VERSION 5.7 ;
  NOWIREEXTENSIONATPIN ON ;
  DIVIDERCHAR "/" ;
  BUSBITCHARS "[]" ;
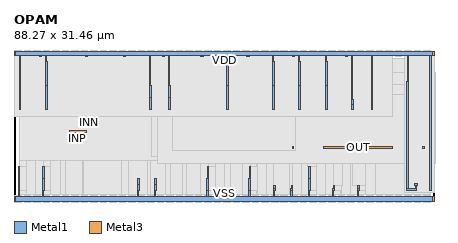
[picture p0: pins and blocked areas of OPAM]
MACRO OPAM
  CLASS BLOCK ;
  FOREIGN OPAM ;
  ORIGIN 1.260 0.000 ;
  SIZE 88.270 BY 31.460 ;
  PIN VSS
    DIRECTION INOUT ;
    USE GROUND ;
    PORT
      LAYER Metal1 ;
        RECT -0.360 4.730 0.000 7.230 ;
        RECT 4.800 4.730 5.160 7.230 ;
        RECT 39.330 4.730 39.690 7.230 ;
        RECT 48.150 4.730 48.510 7.230 ;
        RECT 60.630 4.730 60.990 7.230 ;
        RECT -0.390 2.230 0.000 4.730 ;
        RECT 4.770 2.230 5.160 4.730 ;
        RECT 24.690 3.480 25.050 4.730 ;
        RECT 28.350 3.480 28.710 4.730 ;
        RECT 24.660 2.230 25.050 3.480 ;
        RECT 28.320 2.230 28.710 3.480 ;
        RECT 39.300 2.230 39.690 4.730 ;
        RECT 48.120 2.230 48.510 4.730 ;
        RECT 53.310 2.730 53.670 3.230 ;
        RECT 56.970 2.730 57.330 3.230 ;
        RECT 53.280 2.230 53.670 2.730 ;
        RECT 56.940 2.230 57.330 2.730 ;
        RECT 60.600 2.230 60.990 4.730 ;
        RECT 65.790 2.730 66.150 3.230 ;
        RECT 70.950 2.730 71.310 3.230 ;
        RECT 65.760 2.230 66.150 2.730 ;
        RECT 70.920 2.230 71.310 2.730 ;
        RECT -0.390 0.900 -0.160 2.230 ;
        RECT 4.770 0.900 5.000 2.230 ;
        RECT 24.660 0.900 24.890 2.230 ;
        RECT 28.320 0.900 28.550 2.230 ;
        RECT 39.300 0.900 39.530 2.230 ;
        RECT 48.120 0.900 48.350 2.230 ;
        RECT 53.280 0.900 53.510 2.230 ;
        RECT 56.940 0.900 57.170 2.230 ;
        RECT 60.600 0.900 60.830 2.230 ;
        RECT 65.760 0.900 65.990 2.230 ;
        RECT 70.920 0.900 71.150 2.230 ;
        RECT -1.000 0.000 86.780 0.900 ;
      LAYER Metal3 ;
        RECT -1.260 0.000 87.010 0.900 ;
    END
  END VSS
  PIN VDD
    DIRECTION INOUT ;
    USE POWER ;
    PORT
      LAYER Metal1 ;
        RECT -1.000 30.560 86.780 31.460 ;
        RECT -0.190 29.230 0.040 30.560 ;
        RECT 4.050 30.460 4.530 30.560 ;
        RECT 5.370 29.230 5.600 30.560 ;
        RECT 13.670 30.460 14.150 30.560 ;
        RECT 21.790 30.460 22.270 30.560 ;
        RECT -0.190 24.230 0.200 29.230 ;
        RECT 5.370 24.230 5.760 29.230 ;
        RECT -0.160 19.230 0.200 24.230 ;
        RECT 5.400 19.230 5.760 24.230 ;
        RECT 27.170 24.230 27.400 30.560 ;
        RECT 29.910 30.460 30.390 30.560 ;
        RECT 31.230 24.230 31.460 30.560 ;
        RECT 38.030 30.460 38.510 30.560 ;
        RECT 43.410 29.230 43.640 30.560 ;
        RECT 47.650 30.460 48.130 30.560 ;
        RECT 53.030 29.230 53.260 30.560 ;
        RECT 57.270 30.460 57.750 30.560 ;
        RECT 58.590 29.230 58.820 30.560 ;
        RECT 64.150 29.230 64.380 30.560 ;
        RECT 68.390 30.460 68.870 30.560 ;
        RECT 43.410 24.230 43.800 29.230 ;
        RECT 53.030 24.230 53.420 29.230 ;
        RECT 58.590 24.230 58.980 29.230 ;
        RECT 64.150 24.230 64.540 29.230 ;
        RECT 27.170 21.730 27.560 24.230 ;
        RECT 31.230 21.730 31.620 24.230 ;
        RECT 27.200 19.230 27.560 21.730 ;
        RECT 31.260 19.230 31.620 21.730 ;
        RECT 43.440 19.230 43.800 24.230 ;
        RECT 53.060 19.230 53.420 24.230 ;
        RECT 58.620 19.230 58.980 24.230 ;
        RECT 64.180 19.230 64.540 24.230 ;
        RECT 69.710 21.230 69.940 30.560 ;
        RECT 73.770 29.230 74.000 30.560 ;
        RECT 73.770 24.230 74.160 29.230 ;
        RECT 81.355 25.190 81.585 30.560 ;
        RECT 69.710 20.230 70.100 21.230 ;
        RECT 69.740 19.230 70.100 20.230 ;
        RECT 73.800 19.230 74.160 24.230 ;
        RECT 81.320 2.530 81.620 25.190 ;
        RECT 82.900 3.280 83.600 3.640 ;
        RECT 83.100 2.530 83.400 3.280 ;
        RECT 81.320 2.230 83.400 2.530 ;
        RECT 86.030 2.230 86.510 30.560 ;
      LAYER Metal3 ;
        RECT -1.260 30.560 87.010 31.460 ;
    END
  END VDD
  PIN OUT
    DIRECTION INOUT ;
    ANTENNADIFFAREA 0.748000 ;
    PORT
      LAYER Metal3 ;
      RECT 57.185 11.050 57.585 11.450 ;
      RECT 63.885 11.050 78.385 11.450 ;
      RECT 84.685 11.050 85.085 11.450 ;
    END
  END OUT
  PIN INP
    DIRECTION INPUT ;
    ANTENNAGATEAREA 15.000000 ;
    PORT
      LAYER Metal3 ;
      RECT 10.390 14.350 13.990 14.750 ;
    END
  END INP
  PIN INN
    DIRECTION INPUT ;
    ANTENNAGATEAREA 15.000000 ;
    PORT
      LAYER Metal3 ;
      RECT 12.750 16.330 16.150 16.730 ;
    END
  END INN
  OBS
      LAYER Via1 ;
        RECT -0.160 1.420 86.310 30.040 ;
        RECT 53.260 29.220 54.720 30.040 ;
        RECT 58.820 29.220 60.280 30.040 ;
        RECT 64.380 29.220 65.840 30.040 ;
        RECT 74.000 29.220 75.460 30.040 ;
        RECT 43.640 29.220 45.100 30.040 ;
        RECT 42.850 30.320 44.230 31.700 ;
        RECT 44.850 30.320 46.230 31.700 ;
        RECT 46.850 30.320 48.230 31.700 ;
        RECT 48.850 30.320 50.230 31.700 ;
        RECT 50.850 30.320 52.230 31.700 ;
        RECT 52.850 30.320 54.230 31.700 ;
        RECT 54.850 30.320 56.230 31.700 ;
        RECT 56.850 30.320 58.230 31.700 ;
        RECT 58.850 30.320 60.230 31.700 ;
        RECT 60.850 30.320 62.230 31.700 ;
        RECT 62.850 30.320 64.230 31.700 ;
        RECT 64.850 30.320 66.230 31.700 ;
        RECT 66.850 30.320 68.230 31.700 ;
        RECT 68.850 30.320 70.230 31.700 ;
        RECT 70.850 30.320 72.230 31.700 ;
        RECT 72.850 30.320 74.230 31.700 ;
        RECT 74.850 30.320 76.230 31.700 ;
        RECT 76.850 30.320 78.230 31.700 ;
        RECT 78.850 30.320 80.230 31.700 ;
        RECT 80.850 30.320 82.230 31.700 ;
        RECT 82.850 30.320 84.230 31.700 ;
        RECT 84.850 30.320 86.230 31.700 ;
        RECT 38.850 30.320 40.230 31.700 ;
        RECT 40.850 30.320 42.230 31.700 ;
        RECT 0.040 29.220 1.500 30.040 ;
        RECT 5.600 29.220 7.060 30.040 ;
        RECT -1.150 30.320 0.230 31.700 ;
        RECT 0.850 30.320 2.230 31.700 ;
        RECT 2.850 30.320 4.230 31.700 ;
        RECT 4.850 30.320 6.230 31.700 ;
        RECT 6.850 30.320 8.230 31.700 ;
        RECT 8.850 30.320 10.230 31.700 ;
        RECT 10.850 30.320 12.230 31.700 ;
        RECT 12.850 30.320 14.230 31.700 ;
        RECT 14.850 30.320 16.230 31.700 ;
        RECT 16.850 30.320 18.230 31.700 ;
        RECT 18.850 30.320 20.230 31.700 ;
        RECT 20.850 30.320 22.230 31.700 ;
        RECT 22.850 30.320 24.230 31.700 ;
        RECT 24.850 30.320 26.230 31.700 ;
        RECT 26.850 30.320 28.230 31.700 ;
        RECT 28.850 30.320 30.230 31.700 ;
        RECT 30.850 30.320 32.230 31.700 ;
        RECT 32.850 30.320 34.230 31.700 ;
        RECT 34.850 30.320 36.230 31.700 ;
        RECT 36.850 30.320 38.230 31.700 ;
        RECT 2.850 -0.240 4.230 1.140 ;
        RECT 4.850 -0.240 6.230 1.140 ;
        RECT 6.850 -0.240 8.230 1.140 ;
        RECT 8.850 -0.240 10.230 1.140 ;
        RECT 10.850 -0.240 12.230 1.140 ;
        RECT 12.850 -0.240 14.230 1.140 ;
        RECT 14.850 -0.240 16.230 1.140 ;
        RECT 16.850 -0.240 18.230 1.140 ;
        RECT 18.850 -0.240 20.230 1.140 ;
        RECT 20.850 -0.240 22.230 1.140 ;
        RECT 22.850 -0.240 24.230 1.140 ;
        RECT 24.850 -0.240 26.230 1.140 ;
        RECT 26.850 -0.240 28.230 1.140 ;
        RECT 28.850 -0.240 30.230 1.140 ;
        RECT 30.850 -0.240 32.230 1.140 ;
        RECT 32.850 -0.240 34.230 1.140 ;
        RECT 34.850 -0.240 36.230 1.140 ;
        RECT 36.850 -0.240 38.230 1.140 ;
        RECT 38.850 -0.240 40.230 1.140 ;
        RECT 40.850 -0.240 42.230 1.140 ;
        RECT -0.160 1.420 1.300 2.240 ;
        RECT 5.000 1.420 6.460 2.240 ;
        RECT 39.530 1.420 40.990 2.240 ;
        RECT -1.150 -0.240 0.230 1.140 ;
        RECT 0.850 -0.240 2.230 1.140 ;
        RECT 48.850 -0.240 50.230 1.140 ;
        RECT 50.850 -0.240 52.230 1.140 ;
        RECT 52.850 -0.240 54.230 1.140 ;
        RECT 54.850 -0.240 56.230 1.140 ;
        RECT 56.850 -0.240 58.230 1.140 ;
        RECT 58.850 -0.240 60.230 1.140 ;
        RECT 60.850 -0.240 62.230 1.140 ;
        RECT 62.850 -0.240 64.230 1.140 ;
        RECT 64.850 -0.240 66.230 1.140 ;
        RECT 66.850 -0.240 68.230 1.140 ;
        RECT 68.850 -0.240 70.230 1.140 ;
        RECT 70.850 -0.240 72.230 1.140 ;
        RECT 72.850 -0.240 74.230 1.140 ;
        RECT 74.850 -0.240 76.230 1.140 ;
        RECT 76.850 -0.240 78.230 1.140 ;
        RECT 78.850 -0.240 80.230 1.140 ;
        RECT 80.850 -0.240 82.230 1.140 ;
        RECT 82.850 -0.240 84.230 1.140 ;
        RECT 84.850 -0.240 86.230 1.140 ;
        RECT 42.850 -0.240 44.230 1.140 ;
        RECT 44.850 -0.240 46.230 1.140 ;
        RECT 46.850 -0.240 48.230 1.140 ;
        RECT 48.350 1.420 49.810 2.240 ;
        RECT 60.830 1.420 62.290 2.240 ;
        RECT 65.990 1.420 67.450 2.240 ;
        RECT 71.150 1.420 72.610 2.240 ;
      LAYER Via2 ;
        RECT -1.150 -0.240 0.230 1.140 ;
        RECT 0.850 -0.240 2.230 1.140 ;
        RECT 2.850 -0.240 4.230 1.140 ;
        RECT 4.850 -0.240 6.230 1.140 ;
        RECT 6.850 -0.240 8.230 1.140 ;
        RECT 8.850 -0.240 10.230 1.140 ;
        RECT 10.850 -0.240 12.230 1.140 ;
        RECT 12.850 -0.240 14.230 1.140 ;
        RECT 14.850 -0.240 16.230 1.140 ;
        RECT 16.850 -0.240 18.230 1.140 ;
        RECT 18.850 -0.240 20.230 1.140 ;
        RECT 20.850 -0.240 22.230 1.140 ;
        RECT 22.850 -0.240 24.230 1.140 ;
        RECT 24.850 -0.240 26.230 1.140 ;
        RECT 26.850 -0.240 28.230 1.140 ;
        RECT 28.850 -0.240 30.230 1.140 ;
        RECT 30.850 -0.240 32.230 1.140 ;
        RECT 32.850 -0.240 34.230 1.140 ;
        RECT 34.850 -0.240 36.230 1.140 ;
        RECT 36.850 -0.240 38.230 1.140 ;
        RECT 38.850 -0.240 40.230 1.140 ;
        RECT 40.850 -0.240 42.230 1.140 ;
        RECT 42.850 -0.240 44.230 1.140 ;
        RECT 44.850 -0.240 46.230 1.140 ;
        RECT 46.850 -0.240 48.230 1.140 ;
        RECT 48.850 -0.240 50.230 1.140 ;
        RECT 50.850 -0.240 52.230 1.140 ;
        RECT 52.850 -0.240 54.230 1.140 ;
        RECT 54.850 -0.240 56.230 1.140 ;
        RECT 56.850 -0.240 58.230 1.140 ;
        RECT 58.850 -0.240 60.230 1.140 ;
        RECT 60.850 -0.240 62.230 1.140 ;
        RECT 62.850 -0.240 64.230 1.140 ;
        RECT 64.850 -0.240 66.230 1.140 ;
        RECT 66.850 -0.240 68.230 1.140 ;
        RECT 68.850 -0.240 70.230 1.140 ;
        RECT 70.850 -0.240 72.230 1.140 ;
        RECT 72.850 -0.240 74.230 1.140 ;
        RECT 74.850 -0.240 76.230 1.140 ;
        RECT 76.850 -0.240 78.230 1.140 ;
        RECT 78.850 -0.240 80.230 1.140 ;
        RECT 80.850 -0.240 82.230 1.140 ;
        RECT 82.850 -0.240 84.230 1.140 ;
        RECT 84.850 -0.240 86.230 1.140 ;
        RECT -0.110 8.590 86.310 17.870 ;
        RECT -1.150 30.320 0.230 31.700 ;
        RECT 0.850 30.320 2.230 31.700 ;
        RECT 2.850 30.320 4.230 31.700 ;
        RECT 4.850 30.320 6.230 31.700 ;
        RECT 6.850 30.320 8.230 31.700 ;
        RECT 8.850 30.320 10.230 31.700 ;
        RECT 10.850 30.320 12.230 31.700 ;
        RECT 12.850 30.320 14.230 31.700 ;
        RECT 14.850 30.320 16.230 31.700 ;
        RECT 16.850 30.320 18.230 31.700 ;
        RECT 18.850 30.320 20.230 31.700 ;
        RECT 20.850 30.320 22.230 31.700 ;
        RECT 22.850 30.320 24.230 31.700 ;
        RECT 24.850 30.320 26.230 31.700 ;
        RECT 26.850 30.320 28.230 31.700 ;
        RECT 28.850 30.320 30.230 31.700 ;
        RECT 30.850 30.320 32.230 31.700 ;
        RECT 32.850 30.320 34.230 31.700 ;
        RECT 34.850 30.320 36.230 31.700 ;
        RECT 36.850 30.320 38.230 31.700 ;
        RECT 38.850 30.320 40.230 31.700 ;
        RECT 40.850 30.320 42.230 31.700 ;
        RECT 42.850 30.320 44.230 31.700 ;
        RECT 44.850 30.320 46.230 31.700 ;
        RECT 46.850 30.320 48.230 31.700 ;
        RECT 48.850 30.320 50.230 31.700 ;
        RECT 50.850 30.320 52.230 31.700 ;
        RECT 52.850 30.320 54.230 31.700 ;
        RECT 54.850 30.320 56.230 31.700 ;
        RECT 56.850 30.320 58.230 31.700 ;
        RECT 58.850 30.320 60.230 31.700 ;
        RECT 60.850 30.320 62.230 31.700 ;
        RECT 62.850 30.320 64.230 31.700 ;
        RECT 64.850 30.320 66.230 31.700 ;
        RECT 66.850 30.320 68.230 31.700 ;
        RECT 68.850 30.320 70.230 31.700 ;
        RECT 70.850 30.320 72.230 31.700 ;
        RECT 72.850 30.320 74.230 31.700 ;
        RECT 74.850 30.320 76.230 31.700 ;
        RECT 76.850 30.320 78.230 31.700 ;
        RECT 78.850 30.320 80.230 31.700 ;
        RECT 80.850 30.320 82.230 31.700 ;
        RECT 82.850 30.320 84.230 31.700 ;
        RECT 84.850 30.320 86.230 31.700 ;
      LAYER Via3 ;
        RECT 55.495 9.360 59.275 13.140 ;
        RECT 62.595 8.760 87.375 24.440 ;
        RECT 27.545 9.360 54.625 27.080 ;
      LAYER Via4 ;
        RECT 27.545 7.850 87.375 27.080 ;
      LAYER Metal1 ;
        RECT -0.160 1.420 1.300 2.240 ;
        RECT 5.000 1.420 6.460 2.240 ;
        RECT 39.530 1.420 40.990 2.240 ;
        RECT 48.350 1.420 49.810 2.240 ;
        RECT 60.830 1.420 62.290 2.240 ;
        RECT 65.990 1.420 67.450 2.240 ;
        RECT 71.150 1.420 72.610 2.240 ;
        RECT -0.160 7.220 1.300 9.670 ;
        RECT 5.000 7.220 6.460 9.670 ;
        RECT 39.530 7.220 40.990 9.670 ;
        RECT 57.170 1.420 59.145 10.330 ;
        RECT 62.330 1.420 64.305 10.330 ;
        RECT 1.340 1.420 3.315 10.990 ;
        RECT 6.500 1.420 8.475 10.990 ;
        RECT 44.175 1.420 46.665 11.650 ;
        RECT 48.350 7.220 49.810 11.650 ;
        RECT 49.850 1.420 51.825 11.650 ;
        RECT 72.650 1.420 74.625 12.310 ;
        RECT 20.715 1.420 23.205 12.970 ;
        RECT 67.490 1.420 69.465 13.630 ;
        RECT 41.030 1.420 43.005 14.290 ;
        RECT 31.695 1.420 34.185 16.930 ;
        RECT 0.040 12.830 1.500 19.240 ;
        RECT 5.600 12.830 7.060 19.240 ;
        RECT 43.640 14.810 45.100 19.240 ;
        RECT 58.820 12.830 60.280 19.240 ;
        RECT 64.380 12.830 65.840 19.240 ;
        RECT 74.000 12.830 75.460 19.240 ;
        RECT 69.940 3.220 72.610 22.040 ;
        RECT 22.825 1.420 26.865 25.040 ;
        RECT 27.400 1.420 30.525 25.040 ;
        RECT 31.460 13.490 33.435 25.040 ;
        RECT 35.005 1.420 37.845 25.040 ;
        RECT 39.065 12.170 41.555 25.040 ;
        RECT 82.090 2.000 86.030 25.420 ;
        RECT 0.040 29.220 1.500 30.040 ;
        RECT 1.540 11.510 3.515 30.040 ;
        RECT 5.600 29.220 7.060 30.040 ;
        RECT 7.100 11.510 9.075 30.040 ;
        RECT 9.645 1.420 13.135 30.040 ;
        RECT 13.305 1.420 21.255 30.040 ;
        RECT 43.640 29.220 45.100 30.040 ;
        RECT 45.140 11.510 47.115 30.040 ;
        RECT 48.685 13.490 51.175 30.040 ;
        RECT 53.260 29.220 54.720 30.040 ;
        RECT 53.260 1.420 56.735 30.040 ;
        RECT 58.820 29.220 60.280 30.040 ;
        RECT 60.320 7.220 62.295 30.040 ;
        RECT 64.380 29.220 65.840 30.040 ;
        RECT 65.825 3.220 67.855 30.040 ;
        RECT 74.000 29.220 75.460 30.040 ;
        RECT 75.500 11.510 77.475 30.040 ;
      LAYER Metal2 ;
        RECT -1.150 -0.240 0.230 1.140 ;
        RECT 0.850 -0.240 2.230 1.140 ;
        RECT 2.850 -0.240 4.230 1.140 ;
        RECT 4.850 -0.240 6.230 1.140 ;
        RECT 6.850 -0.240 8.230 1.140 ;
        RECT 8.850 -0.240 10.230 1.140 ;
        RECT 10.850 -0.240 12.230 1.140 ;
        RECT 12.850 -0.240 14.230 1.140 ;
        RECT 14.850 -0.240 16.230 1.140 ;
        RECT 16.850 -0.240 18.230 1.140 ;
        RECT 18.850 -0.240 20.230 1.140 ;
        RECT 20.850 -0.240 22.230 1.140 ;
        RECT 22.850 -0.240 24.230 1.140 ;
        RECT 24.850 -0.240 26.230 1.140 ;
        RECT 26.850 -0.240 28.230 1.140 ;
        RECT 28.850 -0.240 30.230 1.140 ;
        RECT 30.850 -0.240 32.230 1.140 ;
        RECT 32.850 -0.240 34.230 1.140 ;
        RECT 34.850 -0.240 36.230 1.140 ;
        RECT 36.850 -0.240 38.230 1.140 ;
        RECT 38.850 -0.240 40.230 1.140 ;
        RECT 40.850 -0.240 42.230 1.140 ;
        RECT 42.850 -0.240 44.230 1.140 ;
        RECT 44.850 -0.240 46.230 1.140 ;
        RECT 46.850 -0.240 48.230 1.140 ;
        RECT 48.850 -0.240 50.230 1.140 ;
        RECT 50.850 -0.240 52.230 1.140 ;
        RECT 52.850 -0.240 54.230 1.140 ;
        RECT 54.850 -0.240 56.230 1.140 ;
        RECT 56.850 -0.240 58.230 1.140 ;
        RECT 58.850 -0.240 60.230 1.140 ;
        RECT 60.850 -0.240 62.230 1.140 ;
        RECT 62.850 -0.240 64.230 1.140 ;
        RECT 64.850 -0.240 66.230 1.140 ;
        RECT 66.850 -0.240 68.230 1.140 ;
        RECT 68.850 -0.240 70.230 1.140 ;
        RECT 70.850 -0.240 72.230 1.140 ;
        RECT 72.850 -0.240 74.230 1.140 ;
        RECT 74.850 -0.240 76.230 1.140 ;
        RECT 76.850 -0.240 78.230 1.140 ;
        RECT 78.850 -0.240 80.230 1.140 ;
        RECT 80.850 -0.240 82.230 1.140 ;
        RECT 82.850 -0.240 84.230 1.140 ;
        RECT 84.850 -0.240 86.230 1.140 ;
        RECT -0.110 8.590 86.310 17.870 ;
        RECT -1.150 30.320 0.230 31.700 ;
        RECT 0.850 30.320 2.230 31.700 ;
        RECT 2.850 30.320 4.230 31.700 ;
        RECT 4.850 30.320 6.230 31.700 ;
        RECT 6.850 30.320 8.230 31.700 ;
        RECT 8.850 30.320 10.230 31.700 ;
        RECT 10.850 30.320 12.230 31.700 ;
        RECT 12.850 30.320 14.230 31.700 ;
        RECT 14.850 30.320 16.230 31.700 ;
        RECT 16.850 30.320 18.230 31.700 ;
        RECT 18.850 30.320 20.230 31.700 ;
        RECT 20.850 30.320 22.230 31.700 ;
        RECT 22.850 30.320 24.230 31.700 ;
        RECT 24.850 30.320 26.230 31.700 ;
        RECT 26.850 30.320 28.230 31.700 ;
        RECT 28.850 30.320 30.230 31.700 ;
        RECT 30.850 30.320 32.230 31.700 ;
        RECT 32.850 30.320 34.230 31.700 ;
        RECT 34.850 30.320 36.230 31.700 ;
        RECT 36.850 30.320 38.230 31.700 ;
        RECT 38.850 30.320 40.230 31.700 ;
        RECT 40.850 30.320 42.230 31.700 ;
        RECT 42.850 30.320 44.230 31.700 ;
        RECT 44.850 30.320 46.230 31.700 ;
        RECT 46.850 30.320 48.230 31.700 ;
        RECT 48.850 30.320 50.230 31.700 ;
        RECT 50.850 30.320 52.230 31.700 ;
        RECT 52.850 30.320 54.230 31.700 ;
        RECT 54.850 30.320 56.230 31.700 ;
        RECT 56.850 30.320 58.230 31.700 ;
        RECT 58.850 30.320 60.230 31.700 ;
        RECT 60.850 30.320 62.230 31.700 ;
        RECT 62.850 30.320 64.230 31.700 ;
        RECT 64.850 30.320 66.230 31.700 ;
        RECT 66.850 30.320 68.230 31.700 ;
        RECT 68.850 30.320 70.230 31.700 ;
        RECT 70.850 30.320 72.230 31.700 ;
        RECT 72.850 30.320 74.230 31.700 ;
        RECT 74.850 30.320 76.230 31.700 ;
        RECT 76.850 30.320 78.230 31.700 ;
        RECT 78.850 30.320 80.230 31.700 ;
        RECT 80.850 30.320 82.230 31.700 ;
        RECT 82.850 30.320 84.230 31.700 ;
        RECT 84.850 30.320 86.230 31.700 ;
      LAYER Metal3 ;
        RECT 28.745 10.560 30.125 11.940 ;
        RECT 31.645 13.200 33.025 14.580 ;
      LAYER Metal4 ;
        RECT 55.495 9.360 59.275 13.140 ;
        RECT 62.595 8.760 87.375 24.440 ;
        RECT 27.545 9.360 54.625 27.080 ;
      LAYER Metal5 ;
        RECT 28.835 7.850 85.185 22.450 ;
        RECT 32.035 10.650 57.985 25.090 ;
      LAYER Nwell ;
        RECT -1.260 17.750 78.260 31.460 ;
        RECT 80.820 1.730 87.010 31.460 ;
  END
END OPAM
